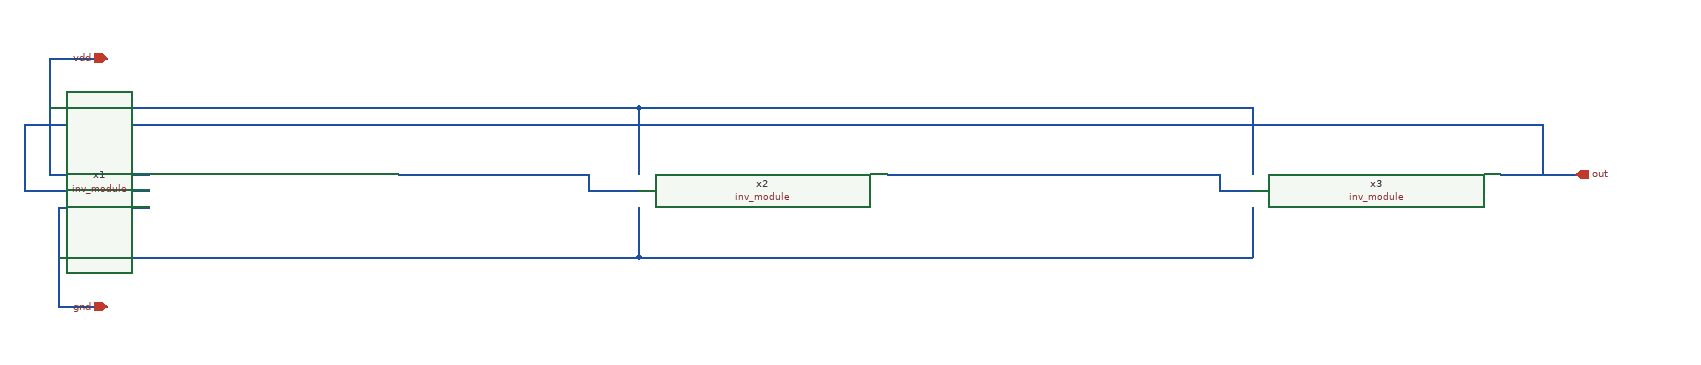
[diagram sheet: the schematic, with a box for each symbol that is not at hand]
v {xschem version=3.4.6RC file_version=1.2
}
G {}
K {}
V {}
S {}
E {}
N 2650 -540 2710 -540 {lab=xxx}
N 2650 -660 2650 -540 {lab=xxx}
N 2650 -660 2760 -660 {lab=xxx}
N 2640 -840 2710 -840 {lab=vdd}
N 2640 -840 2640 -700 {lab=vdd}
N 2640 -700 2760 -700 {lab=vdd}
N 2640 -780 3350 -780 {lab=vdd}
N 3350 -780 4090 -780 {lab=vdd}
N 4090 -780 4090 -700 {lab=vdd}
N 4390 -700 4480 -700 {lab=out}
N 2650 -600 3350 -600 {lab=xxx}
N 3350 -660 3350 -600 {lab=xxx}
N 3350 -600 4090 -600 {lab=xxx}
N 4090 -660 4090 -600 {lab=xxx}
N 4440 -760 4440 -700 {lab=out}
N 4050 -760 4440 -760 {lab=out}
N 4050 -680 4090 -680 {lab=#net1}
N 3290 -760 4050 -760 {lab=out}
N 3290 -680 3350 -680 {lab=#net2}
N 2610 -760 3290 -760 {lab=out}
N 2610 -760 2610 -680 {lab=out}
N 2610 -680 2760 -680 {lab=out}
N 3060 -700 3290 -700 {lab=#net2}
N 3290 -700 3290 -680 {lab=#net2}
N 3650 -700 4050 -700 {lab=#net1}
N 4050 -700 4050 -680 {lab=#net1}
N 3350 -780 3350 -700 {lab=vdd}
C {/home/galihat1704/latihan_inv/inv_module.sym} 2910 -680 0 0 {name=x1}
C {/home/galihat1704/latihan_inv/inv_module.sym} 3500 -680 0 0 {name=x2}
C {/home/galihat1704/latihan_inv/inv_module.sym} 4240 -680 0 0 {name=x3}
C {devices/iopin.sym} 2710 -840 0 0 {name=p1 lab=vdd}
C {devices/iopin.sym} 2710 -540 0 0 {name=p2 lab=gnd}
C {devices/opin.sym} 4480 -700 0 0 {name=p3 lab=out}
